VERSION 5.8 ; BUSBITCHARS "[]" ; DIVIDERCHAR "/" ;
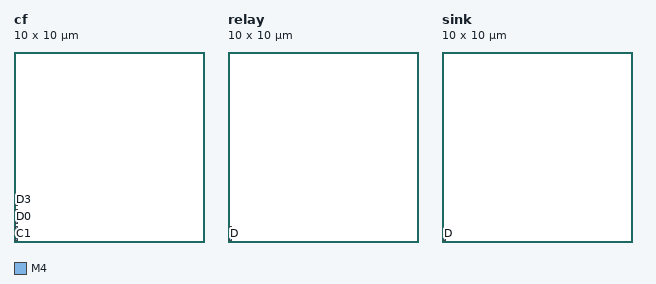
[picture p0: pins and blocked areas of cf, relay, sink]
MACRO cf CLASS BLOCK ; ORIGIN 0 0 ; SIZE 10 BY 10 ; SYMMETRY X Y ;
PIN C0 DIRECTION INPUT ; USE SIGNAL ; PORT LAYER M4 ; RECT 0.1 0.1 0.2 0.2 ; END END C0
PIN C1 DIRECTION INPUT ; USE SIGNAL ; PORT LAYER M4 ; RECT 0.1 0.4 0.2 0.5 ; END END C1
PIN C2 DIRECTION INPUT ; USE SIGNAL ; PORT LAYER M4 ; RECT 0.1 0.7 0.2 0.8 ; END END C2
PIN C3 DIRECTION INPUT ; USE SIGNAL ; PORT LAYER M4 ; RECT 0.1 1.0 0.2 1.1 ; END END C3
PIN D0 DIRECTION INPUT ; USE SIGNAL ; PORT LAYER M4 ; RECT 0.1 1.3 0.2 1.4 ; END END D0
PIN D1 DIRECTION INPUT ; USE SIGNAL ; PORT LAYER M4 ; RECT 0.1 1.6 0.2 1.7 ; END END D1
PIN D2 DIRECTION INPUT ; USE SIGNAL ; PORT LAYER M4 ; RECT 0.1 1.9 0.2 2.0 ; END END D2
PIN D3 DIRECTION INPUT ; USE SIGNAL ; PORT LAYER M4 ; RECT 0.1 2.2 0.2 2.3 ; END END D3
END cf
MACRO relay CLASS BLOCK ; ORIGIN 0 0 ; SIZE 10 BY 10 ; SYMMETRY X Y ;
PIN CK DIRECTION INPUT ; USE SIGNAL ; PORT LAYER M4 ; RECT 0.1 0.1 0.2 0.2 ; END END CK
PIN D DIRECTION INPUT ; USE SIGNAL ; PORT LAYER M4 ; RECT 0.1 0.4 0.2 0.5 ; END END D
PIN CKO DIRECTION OUTPUT ; USE SIGNAL ; PORT LAYER M4 ; RECT 0.1 0.7 0.2 0.8 ; END END CKO
END relay
MACRO sink CLASS BLOCK ; ORIGIN 0 0 ; SIZE 10 BY 10 ; SYMMETRY X Y ;
PIN CK DIRECTION INPUT ; USE SIGNAL ; PORT LAYER M4 ; RECT 0.1 0.1 0.2 0.2 ; END END CK
PIN D DIRECTION INPUT ; USE SIGNAL ; PORT LAYER M4 ; RECT 0.1 0.4 0.2 0.5 ; END END D
END sink
END LIBRARY
